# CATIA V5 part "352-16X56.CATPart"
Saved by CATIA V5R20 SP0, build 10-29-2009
Part number: 352-16X56
Definition: NONE
Nomenclature: 352-16X56
Source: Unknown
Description: 352-16X56
Bounding box of the stored display mesh (mm): x 0 to 56, y -11 to 11, z -11 to 11
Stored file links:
  C:\Users\Utente\Desktop\IO LAVORO\3D X SITO CF\X SITO\PLASTICA\352\352-16X56.CATPart

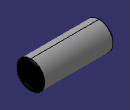
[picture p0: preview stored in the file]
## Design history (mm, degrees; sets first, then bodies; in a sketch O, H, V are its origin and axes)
Body1 "352-16X56" (main body)
  Solid1: solid without history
